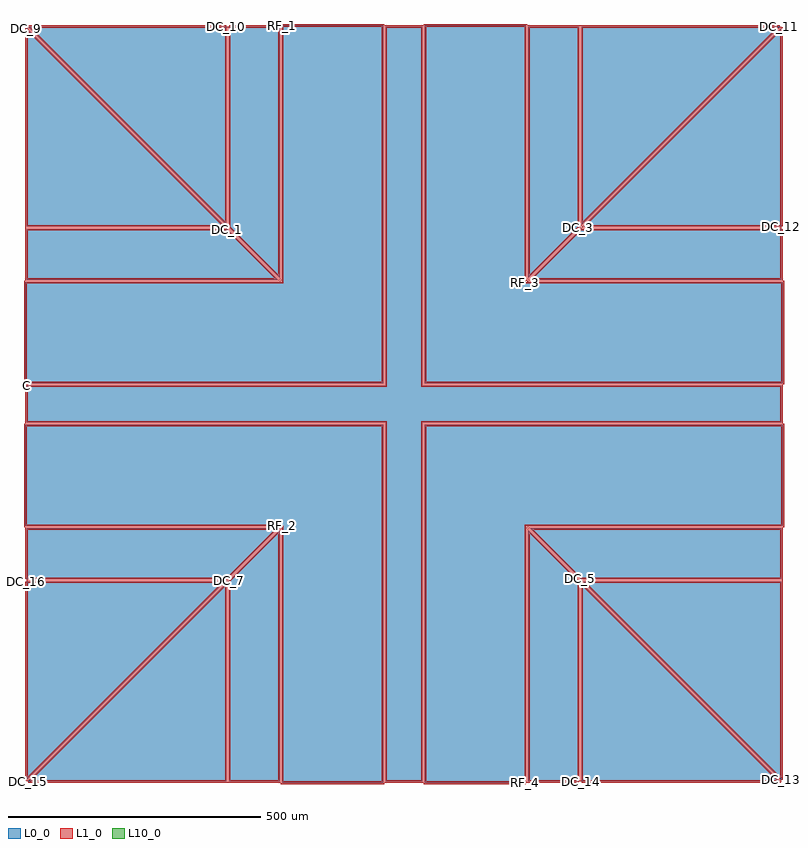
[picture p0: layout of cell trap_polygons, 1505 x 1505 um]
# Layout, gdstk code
import gdstk
lib = gdstk.Library(unit=1e-6, precision=1e-09)
def P(c, l, *ps):  # polygons
    for p in ps: c.add(gdstk.Polygon(p, *l))
L0_0 = (0, 0)
L1_0 = (1, 0)
L10_0 = (10, 0)

trap_polygons = lib.new_cell('trap_polygons')
P(trap_polygons, L0_0, [(-747.5,-351.5),(-355.036,-351.5),(-747.5,-743.964),(-747.5,-351.5)],
  [(-743.964,-747.5),(-351.5,-355.036),(-351.5,-747.5),(-743.964,-747.5)],
  [(351.5,-747.5),(351.5,-355.036),(743.964,-747.5),(351.5,-747.5)],
  [(747.5,-743.964),(355.036,-351.5),(747.5,-351.5),(747.5,-743.964)],
  [(747.5,351.5),(355.036,351.5),(747.5,743.964),(747.5,351.5)],
  [(743.964,747.5),(351.5,355.036),(351.5,747.5),(743.964,747.5)],
  [(-351.5,747.5),(-351.5,355.036),(-743.964,747.5),(-351.5,747.5)],
  [(-747.5,743.964),(-355.036,351.5),(-747.5,351.5),(-747.5,743.964)],
  [(-747.5,-346.5),(-747.5,-246.5),(-250.036,-246.5),(-350.036,-346.5),(-747.5,-346.5)],
  [(-346.5,-350.036),(-246.5,-250.036),(-246.5,-747.5),(-346.5,-747.5),(-346.5,-350.036)],
  [(346.5,-747.5),(246.5,-747.5),(246.5,-250.036),(346.5,-350.036),(346.5,-747.5)],
  [(350.036,-346.5),(250.036,-246.5),(747.5,-246.5),(747.5,-346.5),(350.036,-346.5)],
  [(747.5,346.5),(747.5,246.5),(250.036,246.5),(350.036,346.5),(747.5,346.5)],
  [(346.5,350.036),(246.5,250.036),(246.5,747.5),(346.5,747.5),(346.5,350.036)],
  [(-346.5,747.5),(-246.5,747.5),(-246.5,250.036),(-346.5,350.036),(-346.5,747.5)],
  [(-350.036,346.5),(-250.036,246.5),(-747.5,246.5),(-747.5,346.5),(-350.036,346.5)],
  [(-747.5,36.5),(-36.5,36.5),(-36.5,747.5),(36.5,747.5),(36.5,36.5),(747.5,36.5),(747.5,-36.5),(36.5,-36.5),(36.5,-747.5),(-36.5,-747.5),(-36.5,-36.5),(-747.5,-36.5),(-747.5,36.5)],
  [(241.5,-750),(41.5,-750),(41.5,-41.5),(750,-41.5),(750,-241.5),(241.5,-241.5),(241.5,-750)],
  [(241.5,241.5),(750,241.5),(750,41.5),(41.5,41.5),(41.5,750),(241.5,750),(241.5,241.5)],
  [(-241.5,-241.5),(-750,-241.5),(-750,-41.5),(-41.5,-41.5),(-41.5,-750),(-241.5,-750),(-241.5,-241.5)],
  [(-241.5,750),(-41.5,750),(-41.5,41.5),(-750,41.5),(-750,241.5),(-241.5,241.5),(-241.5,750)])
P(trap_polygons, L1_0, [(-747.5,-349),(-747.5,-354),(-361.071,-354),(-745,-737.929),(-745,-351.5),(-750,-351.5),(-750,-746.464),(-747.5,-747.5),(-351.5,-351.5),(-352.536,-349)],
  [(-745.732,-745.732),(-742.197,-749.268),(-354,-361.071),(-354,-745),(-743.964,-745),(-743.964,-750),(-349,-750),(-349,-352.536),(-351.5,-351.5)],
  [(349,-747.5),(354,-747.5),(354,-361.071),(737.929,-745),(351.5,-745),(351.5,-750),(746.464,-750),(747.5,-747.5),(351.5,-351.5),(349,-352.536)],
  [(745.732,-745.732),(749.268,-742.197),(361.071,-354),(745,-354),(745,-743.964),(750,-743.964),(750,-349),(352.536,-349),(351.5,-351.5)],
  [(747.5,349),(747.5,354),(361.071,354),(745,737.929),(745,351.5),(750,351.5),(750,746.464),(747.5,747.5),(351.5,351.5),(352.536,349)],
  [(745.732,745.732),(742.197,749.268),(354,361.071),(354,745),(743.964,745),(743.964,750),(349,750),(349,352.536),(351.5,351.5)],
  [(-349,747.5),(-354,747.5),(-354,361.071),(-737.929,745),(-351.5,745),(-351.5,750),(-746.464,750),(-747.5,747.5),(-351.5,351.5),(-349,352.536)],
  [(-745.732,745.732),(-749.268,742.197),(-361.071,354),(-745,354),(-745,743.964),(-750,743.964),(-750,349),(-352.536,349),(-351.5,351.5)],
  [(-750,-346.5),(-745,-346.5),(-745,-249),(-256.071,-249),(-351.071,-344),(-747.5,-344),(-747.5,-349),(-349,-349),(-246.5,-246.5),(-247.536,-244),(-750,-244)],
  [(-348.268,-348.268),(-344.732,-351.803),(-249,-256.071),(-249,-745),(-344,-745),(-344,-350.036),(-349,-350.036),(-349,-750),(-244,-750),(-244,-247.536),(-246.5,-246.5)],
  [(346.5,-750),(346.5,-745),(249,-745),(249,-256.071),(344,-351.071),(344,-747.5),(349,-747.5),(349,-349),(246.5,-246.5),(244,-247.536),(244,-750)],
  [(348.268,-348.268),(351.803,-344.732),(256.071,-249),(745,-249),(745,-344),(350.036,-344),(350.036,-349),(750,-349),(750,-244),(247.536,-244),(246.5,-246.5)],
  [(750,346.5),(745,346.5),(745,249),(256.071,249),(351.071,344),(747.5,344),(747.5,349),(349,349),(246.5,246.5),(247.536,244),(750,244)],
  [(348.268,348.268),(344.732,351.803),(249,256.071),(249,745),(344,745),(344,350.036),(349,350.036),(349,750),(244,750),(244,247.536),(246.5,246.5)],
  [(-346.5,750),(-346.5,745),(-249,745),(-249,256.071),(-344,351.071),(-344,747.5),(-349,747.5),(-349,349),(-246.5,246.5),(-244,247.536),(-244,750)],
  [(-348.268,348.268),(-351.803,344.732),(-256.071,249),(-745,249),(-745,344),(-350.036,344),(-350.036,349),(-750,349),(-750,244),(-247.536,244),(-246.5,246.5)],
  [(-747.5,39),(-747.5,34),(-34,34),(-34,745),(34,745),(34,34),(745,34),(745,-34),(34,-34),(34,-745),(-34,-745),(-34,-34),(-745,-34),(-745,36.5),(-750,36.5),(-750,-39),(-39,-39),(-39,-750),(39,-750),(39,-39),(750,-39),(750,39),(39,39),(39,750),(-39,750),(-39,39)],
  [(241.5,-752.5),(241.5,-747.5),(44,-747.5),(44,-44),(747.5,-44),(747.5,-239),(239,-239),(239,-750),(244,-750),(244,-244),(752.5,-244),(752.5,-39),(39,-39),(39,-752.5)],
  [(241.5,244),(241.5,239),(747.5,239),(747.5,44),(44,44),(44,747.5),(239,747.5),(239,241.5),(244,241.5),(244,752.5),(39,752.5),(39,39),(752.5,39),(752.5,244)],
  [(-241.5,-244),(-241.5,-239),(-747.5,-239),(-747.5,-44),(-44,-44),(-44,-747.5),(-239,-747.5),(-239,-241.5),(-244,-241.5),(-244,-752.5),(-39,-752.5),(-39,-39),(-752.5,-39),(-752.5,-244)],
  [(-241.5,752.5),(-241.5,747.5),(-44,747.5),(-44,44),(-747.5,44),(-747.5,239),(-239,239),(-239,750),(-244,750),(-244,244),(-752.5,244),(-752.5,39),(-39,39),(-39,752.5)])
P(trap_polygons, L10_0, [(0,0),(0,0),(0,0),(0,0)])
trap_polygons.add(gdstk.Label('DC_16', (-747.5,-351.5), layer=2, texttype=0))
trap_polygons.add(gdstk.Label('DC_15', (-743.964,-747.5), layer=2, texttype=0))
trap_polygons.add(gdstk.Label('DC_14', (351.5,-747.5), layer=2, texttype=0))
trap_polygons.add(gdstk.Label('DC_13', (747.5,-743.964), layer=2, texttype=0))
trap_polygons.add(gdstk.Label('DC_12', (747.5,351.5), layer=2, texttype=0))
trap_polygons.add(gdstk.Label('DC_11', (743.964,747.5), layer=2, texttype=0))
trap_polygons.add(gdstk.Label('DC_10', (-351.5,747.5), layer=2, texttype=0))
trap_polygons.add(gdstk.Label('DC_9', (-747.5,743.964), layer=2, texttype=0))
trap_polygons.add(gdstk.Label('DC_8', (-747.5,-346.5), layer=2, texttype=0))
trap_polygons.add(gdstk.Label('DC_7', (-346.5,-350.036), layer=2, texttype=0))
trap_polygons.add(gdstk.Label('DC_6', (346.5,-747.5), layer=2, texttype=0))
trap_polygons.add(gdstk.Label('DC_5', (350.036,-346.5), layer=2, texttype=0))
trap_polygons.add(gdstk.Label('DC_4', (747.5,346.5), layer=2, texttype=0))
trap_polygons.add(gdstk.Label('DC_3', (346.5,350.036), layer=2, texttype=0))
trap_polygons.add(gdstk.Label('DC_2', (-346.5,747.5), layer=2, texttype=0))
trap_polygons.add(gdstk.Label('DC_1', (-350.036,346.5), layer=2, texttype=0))
trap_polygons.add(gdstk.Label('C', (-747.5,36.5), layer=2, texttype=0))
trap_polygons.add(gdstk.Label('RF_4', (241.5,-750), layer=2, texttype=0))
trap_polygons.add(gdstk.Label('RF_3', (241.5,241.5), layer=2, texttype=0))
trap_polygons.add(gdstk.Label('RF_2', (-241.5,-241.5), layer=2, texttype=0))
trap_polygons.add(gdstk.Label('RF_1', (-241.5,750), layer=2, texttype=0))

lib.write_gds('trap_polygons.gds')
